VERSION 5.8 ;
BUSBITCHARS "[]" ;
DIVIDERCHAR "/" ;
UNITS
    DATABASE MICRONS 1000 ;
END UNITS

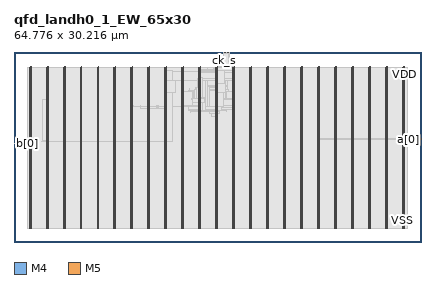
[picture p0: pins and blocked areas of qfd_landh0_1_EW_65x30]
MACRO qfd_landh0_1_EW_65x30
  FOREIGN qfd_landh0_1_EW_65x30 0 0 ;
  CLASS BLOCK ;
  SIZE 64.776 BY 30.216 ;
  PIN a[0]
    DIRECTION INPUT ;
    USE SIGNAL ;
    PORT
      LAYER M4 ;
        RECT  64.692 16.368 64.776 16.392 ;
    END
  END a[0]
  PIN b[0]
    DIRECTION OUTPUT ;
    USE SIGNAL ;
    PORT
      LAYER M4 ;
        RECT  0 15.6 0.084 15.624 ;
    END
  END b[0]
  PIN ck
    DIRECTION INPUT ;
    USE SIGNAL ;
    PORT
      LAYER M5 ;
        RECT  33.36 30.132 33.384 30.216 ;
    END
  END ck
  PIN ck_s
    DIRECTION INPUT ;
    USE SIGNAL ;
    PORT
      LAYER M5 ;
        RECT  33.456 30.132 33.48 30.216 ;
    END
  END ck_s
  PIN en
    DIRECTION INPUT ;
    USE SIGNAL ;
    PORT
      LAYER M5 ;
        RECT  33.552 30.132 33.576 30.216 ;
    END
  END en
  PIN fault
    DIRECTION OUTPUT ;
    USE SIGNAL ;
    PORT
      LAYER M5 ;
        RECT  33.648 30.132 33.672 30.216 ;
    END
  END fault
  PIN k0
    DIRECTION INPUT ;
    USE SIGNAL ;
    PORT
      LAYER M5 ;
        RECT  33.744 30.132 33.768 30.216 ;
    END
  END k0
  PIN k1
    DIRECTION INPUT ;
    USE SIGNAL ;
    PORT
      LAYER M5 ;
        RECT  33.84 30.132 33.864 30.216 ;
    END
  END k1
  PIN k2
    DIRECTION INPUT ;
    USE SIGNAL ;
    PORT
      LAYER M5 ;
        RECT  33.936 30.132 33.96 30.216 ;
    END
  END k2
  PIN rs
    DIRECTION INPUT ;
    USE SIGNAL ;
    PORT
      LAYER M5 ;
        RECT  34.032 30.132 34.056 30.216 ;
    END
  END rs
  PIN tie_hi
    DIRECTION OUTPUT ;
    USE SIGNAL ;
    PORT
      LAYER M5 ;
        RECT  34.128 30.132 34.152 30.216 ;
    END
  END tie_hi
  PIN tie_lo
    DIRECTION OUTPUT ;
    USE SIGNAL ;
    PORT
      LAYER M5 ;
        RECT  34.224 30.132 34.248 30.216 ;
    END
  END tie_lo
  PIN VDD
    DIRECTION INOUT ;
    USE POWER ;
    PORT
      LAYER M5 ;
        RECT  61.992 2.151 62.112 27.833 ;
        RECT  59.292 2.151 59.412 27.833 ;
        RECT  56.592 2.151 56.712 27.833 ;
        RECT  53.892 2.151 54.012 27.833 ;
        RECT  51.192 2.151 51.312 27.833 ;
        RECT  48.492 2.151 48.612 27.833 ;
        RECT  45.792 2.151 45.912 27.833 ;
        RECT  43.092 2.151 43.212 27.833 ;
        RECT  40.392 2.151 40.512 27.833 ;
        RECT  37.692 2.151 37.812 27.833 ;
        RECT  34.992 2.151 35.112 27.833 ;
        RECT  32.292 2.151 32.412 27.833 ;
        RECT  29.592 2.151 29.712 27.833 ;
        RECT  26.892 2.151 27.012 27.833 ;
        RECT  24.192 2.151 24.312 27.833 ;
        RECT  21.492 2.151 21.612 27.833 ;
        RECT  18.792 2.151 18.912 27.833 ;
        RECT  16.092 2.151 16.212 27.833 ;
        RECT  13.392 2.151 13.512 27.833 ;
        RECT  10.692 2.151 10.812 27.833 ;
        RECT  7.992 2.151 8.112 27.833 ;
        RECT  5.292 2.151 5.412 27.833 ;
        RECT  2.592 2.151 2.712 27.833 ;
    END
  END VDD
  PIN VSS
    DIRECTION INOUT ;
    USE GROUND ;
    PORT
      LAYER M5 ;
        RECT  61.8 2.137 61.92 27.819 ;
        RECT  59.1 2.137 59.22 27.819 ;
        RECT  56.4 2.137 56.52 27.819 ;
        RECT  53.7 2.137 53.82 27.819 ;
        RECT  51 2.137 51.12 27.819 ;
        RECT  48.3 2.137 48.42 27.819 ;
        RECT  45.6 2.137 45.72 27.819 ;
        RECT  42.9 2.137 43.02 27.819 ;
        RECT  40.2 2.137 40.32 27.819 ;
        RECT  37.5 2.137 37.62 27.819 ;
        RECT  34.8 2.137 34.92 27.819 ;
        RECT  32.1 2.137 32.22 27.819 ;
        RECT  29.4 2.137 29.52 27.819 ;
        RECT  26.7 2.137 26.82 27.819 ;
        RECT  24 2.137 24.12 27.819 ;
        RECT  21.3 2.137 21.42 27.819 ;
        RECT  18.6 2.137 18.72 27.819 ;
        RECT  15.9 2.137 16.02 27.819 ;
        RECT  13.2 2.137 13.32 27.819 ;
        RECT  10.5 2.137 10.62 27.819 ;
        RECT  7.8 2.137 7.92 27.819 ;
        RECT  5.1 2.137 5.22 27.819 ;
        RECT  2.4 2.137 2.52 27.819 ;
    END
  END VSS
  OBS
    LAYER RVTN ;
     RECT  2.16 2.16 62.586 2.295 ;
     RECT  2.16 2.565 62.586 2.835 ;
     RECT  2.16 3.105 62.586 3.375 ;
     RECT  2.16 3.645 62.586 3.915 ;
     RECT  2.16 4.185 62.586 4.455 ;
     RECT  2.16 4.725 62.586 4.995 ;
     RECT  2.16 5.265 62.586 5.535 ;
     RECT  2.16 5.805 62.586 6.075 ;
     RECT  2.16 6.345 62.586 6.615 ;
     RECT  2.16 6.885 62.586 7.155 ;
     RECT  2.16 7.425 62.586 7.695 ;
     RECT  2.16 7.965 62.586 8.235 ;
     RECT  2.16 8.505 62.586 8.775 ;
     RECT  2.16 9.045 62.586 9.315 ;
     RECT  2.16 9.585 62.586 9.855 ;
     RECT  2.16 10.125 62.586 10.395 ;
     RECT  2.16 10.665 62.586 10.935 ;
     RECT  2.16 11.205 62.586 11.475 ;
     RECT  2.16 11.745 62.586 12.015 ;
     RECT  2.16 12.285 62.586 12.555 ;
     RECT  2.16 12.825 62.586 13.095 ;
     RECT  2.16 13.365 62.586 13.635 ;
     RECT  2.16 13.905 62.586 14.175 ;
     RECT  2.16 14.445 62.586 14.715 ;
     RECT  2.16 14.985 62.586 15.255 ;
     RECT  2.16 15.525 62.586 15.795 ;
     RECT  2.16 16.065 62.586 16.335 ;
     RECT  2.16 16.605 62.586 16.875 ;
     RECT  2.16 17.145 62.586 17.415 ;
     RECT  2.16 17.685 62.586 17.955 ;
     RECT  2.16 18.225 62.586 18.495 ;
     RECT  2.16 18.765 62.586 19.035 ;
     RECT  2.16 19.305 62.586 19.575 ;
     RECT  2.16 19.845 62.586 20.115 ;
     RECT  2.16 20.385 62.586 20.655 ;
     RECT  2.16 20.925 62.586 21.195 ;
     RECT  2.16 21.465 62.586 21.735 ;
     RECT  2.16 22.005 62.586 22.275 ;
     RECT  2.16 22.545 62.586 22.815 ;
     RECT  2.16 23.085 62.586 23.355 ;
     RECT  2.16 23.625 62.586 23.895 ;
     RECT  2.16 24.165 62.586 24.435 ;
     RECT  2.16 24.705 62.586 24.975 ;
     RECT  2.16 25.245 62.586 25.515 ;
     RECT  2.16 25.785 62.586 26.055 ;
     RECT  2.16 26.325 62.586 26.595 ;
     RECT  2.16 26.865 62.586 27.135 ;
     RECT  2.16 27.405 62.586 27.675 ;
    LAYER RVTP ;
     RECT  2.16 2.295 62.586 2.565 ;
     RECT  2.16 2.835 62.586 3.105 ;
     RECT  2.16 3.375 62.586 3.645 ;
     RECT  2.16 3.915 62.586 4.185 ;
     RECT  2.16 4.455 62.586 4.725 ;
     RECT  2.16 4.995 62.586 5.265 ;
     RECT  2.16 5.535 62.586 5.805 ;
     RECT  2.16 6.075 62.586 6.345 ;
     RECT  2.16 6.615 62.586 6.885 ;
     RECT  2.16 7.155 62.586 7.425 ;
     RECT  2.16 7.695 62.586 7.965 ;
     RECT  2.16 8.235 62.586 8.505 ;
     RECT  2.16 8.775 62.586 9.045 ;
     RECT  2.16 9.315 62.586 9.585 ;
     RECT  2.16 9.855 62.586 10.125 ;
     RECT  2.16 10.395 62.586 10.665 ;
     RECT  2.16 10.935 62.586 11.205 ;
     RECT  2.16 11.475 62.586 11.745 ;
     RECT  2.16 12.015 62.586 12.285 ;
     RECT  2.16 12.555 62.586 12.825 ;
     RECT  2.16 13.095 62.586 13.365 ;
     RECT  2.16 13.635 62.586 13.905 ;
     RECT  2.16 14.175 62.586 14.445 ;
     RECT  2.16 14.715 62.586 14.985 ;
     RECT  2.16 15.255 62.586 15.525 ;
     RECT  2.16 15.795 62.586 16.065 ;
     RECT  2.16 16.335 62.586 16.605 ;
     RECT  2.16 16.875 62.586 17.145 ;
     RECT  2.16 17.415 62.586 17.685 ;
     RECT  2.16 17.955 62.586 18.225 ;
     RECT  2.16 18.495 62.586 18.765 ;
     RECT  2.16 19.035 62.586 19.305 ;
     RECT  2.16 19.575 62.586 19.845 ;
     RECT  2.16 20.115 62.586 20.385 ;
     RECT  2.16 20.655 62.586 20.925 ;
     RECT  2.16 21.195 62.586 21.465 ;
     RECT  2.16 21.735 62.586 22.005 ;
     RECT  2.16 22.275 62.586 22.545 ;
     RECT  2.16 22.815 62.586 23.085 ;
     RECT  2.16 23.355 62.586 23.625 ;
     RECT  2.16 23.895 62.586 24.165 ;
     RECT  2.16 24.435 62.586 24.705 ;
     RECT  2.16 24.975 62.586 25.245 ;
     RECT  2.16 25.515 62.586 25.785 ;
     RECT  2.16 26.055 62.586 26.325 ;
     RECT  2.16 26.595 62.586 26.865 ;
     RECT  2.16 27.135 62.586 27.405 ;
     RECT  2.16 27.675 62.586 27.81 ;
    LAYER M1 ;
     RECT  2.16 2.151 62.586 27.819 ;
    LAYER M2 ;
     RECT  2.16 2.151 62.586 27.819 ;
    LAYER M3 ;
     RECT  2.415 2.143 2.505 2.413 ;
     RECT  5.115 2.143 5.205 2.413 ;
     RECT  7.815 2.143 7.905 2.413 ;
     RECT  10.515 2.143 10.605 2.413 ;
     RECT  13.215 2.143 13.305 2.413 ;
     RECT  15.915 2.143 16.005 2.413 ;
     RECT  18.615 2.143 18.705 2.413 ;
     RECT  21.315 2.143 21.405 2.413 ;
     RECT  24.015 2.143 24.105 2.413 ;
     RECT  26.715 2.143 26.805 2.413 ;
     RECT  29.415 2.143 29.505 2.413 ;
     RECT  32.115 2.143 32.205 2.413 ;
     RECT  34.815 2.143 34.905 2.413 ;
     RECT  37.515 2.143 37.605 2.413 ;
     RECT  40.215 2.143 40.305 2.413 ;
     RECT  42.915 2.143 43.005 2.413 ;
     RECT  45.615 2.143 45.705 2.413 ;
     RECT  48.315 2.143 48.405 2.413 ;
     RECT  51.015 2.143 51.105 2.413 ;
     RECT  53.715 2.143 53.805 2.413 ;
     RECT  56.415 2.143 56.505 2.413 ;
     RECT  59.115 2.143 59.205 2.413 ;
     RECT  61.815 2.143 61.905 2.413 ;
     RECT  2.415 2.413 2.697 15.595 ;
     RECT  2.304 15.595 2.697 15.827 ;
     RECT  4.32 15.961 4.338 16.013 ;
     RECT  5.115 2.413 5.397 16.141 ;
     RECT  48.315 2.413 48.597 16.363 ;
     RECT  32.115 2.413 32.397 18.121 ;
     RECT  48.276 16.363 48.597 18.185 ;
     RECT  32.004 18.121 32.397 19.921 ;
     RECT  31.392 19.921 32.397 20.425 ;
     RECT  31.14 20.425 32.397 20.461 ;
     RECT  28.008 20.623 28.026 20.731 ;
     RECT  29.415 2.413 29.697 20.731 ;
     RECT  31.14 20.461 32.67 20.731 ;
     RECT  33.804 20.731 33.822 20.893 ;
     RECT  28.008 20.731 32.67 20.929 ;
     RECT  33.624 20.893 33.822 20.929 ;
     RECT  27.828 20.929 33.822 21.001 ;
     RECT  34.815 2.413 35.097 21.001 ;
     RECT  18.615 2.413 18.897 21.499 ;
     RECT  22.788 21.211 22.806 21.499 ;
     RECT  22.68 21.499 22.914 21.629 ;
     RECT  18.615 21.499 18.99 21.659 ;
     RECT  20.088 21.211 20.106 21.659 ;
     RECT  27.828 21.001 35.097 21.677 ;
     RECT  4.464 16.141 5.397 22.649 ;
     RECT  28.332 21.677 35.097 22.741 ;
     RECT  28.224 22.741 35.097 22.781 ;
     RECT  25.632 23.791 25.65 23.837 ;
     RECT  24.015 2.413 24.297 23.851 ;
     RECT  28.332 22.781 35.097 23.855 ;
     RECT  33.12 23.855 35.097 23.927 ;
     RECT  28.332 23.855 32.397 23.947 ;
     RECT  24.015 23.851 24.498 24.091 ;
     RECT  27.792 23.947 32.397 24.125 ;
     RECT  24.015 24.091 25.038 24.131 ;
     RECT  28.728 24.125 32.397 24.221 ;
     RECT  33.12 23.927 34.074 24.269 ;
     RECT  27.936 24.125 27.954 24.359 ;
     RECT  28.836 24.221 32.397 24.503 ;
     RECT  29.088 24.503 32.397 24.509 ;
     RECT  29.124 24.509 32.397 24.781 ;
     RECT  33.12 24.269 34.002 24.781 ;
     RECT  24.015 24.131 24.498 24.859 ;
     RECT  24.015 24.859 25.146 24.899 ;
     RECT  24.015 24.899 24.498 24.935 ;
     RECT  29.124 24.781 34.002 24.935 ;
     RECT  29.232 24.935 34.002 25.717 ;
     RECT  34.815 23.927 35.097 25.717 ;
     RECT  28.98 25.717 35.097 25.757 ;
     RECT  29.232 25.757 35.097 25.979 ;
     RECT  29.415 25.979 35.097 26.051 ;
     RECT  29.415 26.051 32.397 26.905 ;
     RECT  33.156 26.051 35.097 26.905 ;
     RECT  29.415 26.905 35.097 27.329 ;
     RECT  29.415 27.329 32.49 27.365 ;
     RECT  30.564 27.365 30.762 27.401 ;
     RECT  31.536 27.365 32.397 27.509 ;
     RECT  2.415 15.827 2.697 27.557 ;
     RECT  5.115 22.649 5.397 27.557 ;
     RECT  7.815 2.413 8.097 27.557 ;
     RECT  10.515 2.413 10.797 27.557 ;
     RECT  13.215 2.413 13.497 27.557 ;
     RECT  15.915 2.413 16.197 27.557 ;
     RECT  18.615 21.659 18.897 27.557 ;
     RECT  21.315 2.413 21.597 27.557 ;
     RECT  24.015 24.935 24.297 27.557 ;
     RECT  26.715 2.413 26.997 27.557 ;
     RECT  29.415 27.365 29.697 27.557 ;
     RECT  33.228 27.329 35.097 27.557 ;
     RECT  37.515 2.413 37.797 27.557 ;
     RECT  40.215 2.413 40.497 27.557 ;
     RECT  42.915 2.413 43.197 27.557 ;
     RECT  45.615 2.413 45.897 27.557 ;
     RECT  48.315 18.185 48.597 27.557 ;
     RECT  51.015 2.413 51.297 27.557 ;
     RECT  53.715 2.413 53.997 27.557 ;
     RECT  56.415 2.413 56.697 27.557 ;
     RECT  59.115 2.413 59.397 27.557 ;
     RECT  61.815 2.413 62.097 27.557 ;
     RECT  33.228 27.557 34.254 27.599 ;
     RECT  31.68 27.509 32.397 27.635 ;
     RECT  30.744 27.401 30.762 27.707 ;
     RECT  32.076 27.635 32.397 27.707 ;
     RECT  2.607 27.557 2.697 27.827 ;
     RECT  5.307 27.557 5.397 27.827 ;
     RECT  8.007 27.557 8.097 27.827 ;
     RECT  10.707 27.557 10.797 27.827 ;
     RECT  13.407 27.557 13.497 27.827 ;
     RECT  16.107 27.557 16.197 27.827 ;
     RECT  18.807 27.557 18.897 27.827 ;
     RECT  21.507 27.557 21.597 27.827 ;
     RECT  24.207 27.557 24.297 27.827 ;
     RECT  26.907 27.557 26.997 27.827 ;
     RECT  29.607 27.557 29.697 27.827 ;
     RECT  32.307 27.707 32.397 27.827 ;
     RECT  35.007 27.557 35.097 27.827 ;
     RECT  37.707 27.557 37.797 27.827 ;
     RECT  40.407 27.557 40.497 27.827 ;
     RECT  43.107 27.557 43.197 27.827 ;
     RECT  45.807 27.557 45.897 27.827 ;
     RECT  48.507 27.557 48.597 27.827 ;
     RECT  51.207 27.557 51.297 27.827 ;
     RECT  53.907 27.557 53.997 27.827 ;
     RECT  56.607 27.557 56.697 27.827 ;
     RECT  59.307 27.557 59.397 27.827 ;
     RECT  62.007 27.557 62.097 27.827 ;
     RECT  33.552 27.599 34.254 27.965 ;
     RECT  33.624 27.965 34.254 30.029 ;
     RECT  33.624 30.029 34.218 30.125 ;
    LAYER M4 ;
     RECT  0.06 15.6 2.408 15.624 ;
     RECT  2.408 2.148 2.512 27.552 ;
     RECT  2.512 2.418 2.6 27.552 ;
     RECT  2.6 2.418 2.704 27.822 ;
     RECT  4.309 15.984 5.108 16.008 ;
     RECT  5.108 2.148 5.212 27.552 ;
     RECT  5.212 2.418 5.3 27.552 ;
     RECT  5.3 2.418 5.404 27.822 ;
     RECT  5.404 15.984 7.808 16.008 ;
     RECT  7.808 2.148 7.912 27.552 ;
     RECT  7.912 2.418 8 27.552 ;
     RECT  8 2.418 8.104 27.822 ;
     RECT  8.104 15.984 10.508 16.008 ;
     RECT  10.508 2.148 10.612 27.552 ;
     RECT  10.612 2.418 10.7 27.552 ;
     RECT  10.7 2.418 10.804 27.822 ;
     RECT  10.804 15.984 13.208 16.008 ;
     RECT  13.208 2.148 13.312 27.552 ;
     RECT  13.312 2.418 13.4 27.552 ;
     RECT  13.4 2.418 13.504 27.822 ;
     RECT  13.504 15.984 15.908 16.008 ;
     RECT  15.908 2.148 16.012 27.552 ;
     RECT  16.012 2.418 16.1 27.552 ;
     RECT  16.1 2.418 16.204 27.822 ;
     RECT  16.204 15.984 18.608 16.008 ;
     RECT  18.608 2.148 18.712 27.552 ;
     RECT  18.712 2.418 18.8 27.552 ;
     RECT  18.8 2.418 18.904 27.822 ;
     RECT  18.904 21.504 20.077 21.528 ;
     RECT  18.904 15.984 21.308 16.008 ;
     RECT  20.077 21.216 21.308 21.528 ;
     RECT  21.308 2.148 21.412 27.552 ;
     RECT  21.412 2.418 21.5 27.552 ;
     RECT  21.5 2.418 21.604 27.822 ;
     RECT  21.604 21.216 22.669 21.528 ;
     RECT  22.669 21.216 22.925 21.624 ;
     RECT  21.604 15.984 24.008 16.008 ;
     RECT  22.925 21.216 24.008 21.528 ;
     RECT  24.008 2.148 24.112 27.552 ;
     RECT  24.112 2.418 24.2 27.552 ;
     RECT  24.2 2.418 24.304 27.822 ;
     RECT  24.304 21.216 24.467 21.528 ;
     RECT  24.304 23.856 24.509 24.888 ;
     RECT  24.304 15.984 25.187 16.008 ;
     RECT  24.509 24.096 25.187 24.888 ;
     RECT  25.187 24.096 25.58 24.12 ;
     RECT  25.58 23.808 25.667 24.12 ;
     RECT  24.467 21.504 26.708 21.528 ;
     RECT  25.621 25.728 26.708 25.752 ;
     RECT  24.304 27.168 26.708 27.192 ;
     RECT  26.708 2.148 26.812 27.552 ;
     RECT  26.812 2.418 26.9 27.552 ;
     RECT  26.9 2.418 27.004 27.822 ;
     RECT  28.213 22.752 28.501 22.776 ;
     RECT  27.004 23.952 28.501 23.976 ;
     RECT  28.501 22.752 28.717 23.976 ;
     RECT  28.717 22.752 29.077 24.216 ;
     RECT  29.077 22.752 29.269 24.504 ;
     RECT  27.004 25.728 29.269 25.752 ;
     RECT  27.004 21.504 29.408 21.672 ;
     RECT  29.269 22.752 29.408 26.136 ;
     RECT  27.004 27.168 29.408 27.192 ;
     RECT  29.408 2.148 29.512 27.552 ;
     RECT  29.512 2.418 29.6 27.552 ;
     RECT  29.6 2.418 29.704 27.822 ;
     RECT  29.704 20.88 30.017 26.136 ;
     RECT  30.017 20.88 30.449 25.752 ;
     RECT  30.449 21.504 30.809 25.752 ;
     RECT  30.809 21.504 31.133 24.696 ;
     RECT  29.704 27.168 31.993 27.192 ;
     RECT  31.133 21.504 32.108 24.024 ;
     RECT  30.809 25.728 32.108 25.752 ;
     RECT  31.993 26.736 32.108 27.192 ;
     RECT  32.108 2.148 32.212 27.552 ;
     RECT  32.212 2.418 32.3 27.552 ;
     RECT  32.3 2.418 32.404 27.822 ;
     RECT  32.404 20.976 32.573 23.928 ;
     RECT  32.573 20.976 33.011 22.824 ;
     RECT  33.011 20.976 33.052 21.528 ;
     RECT  32.404 25.728 33.244 26.616 ;
     RECT  33.052 21.408 33.395 21.528 ;
     RECT  33.244 25.728 33.469 25.752 ;
     RECT  32.573 23.904 33.491 23.928 ;
     RECT  33.5 27.936 33.587 27.96 ;
     RECT  33.011 22.752 33.589 22.824 ;
     RECT  33.469 25.104 33.635 25.752 ;
     RECT  33.613 30.096 33.649 30.12 ;
     RECT  33.635 25.728 33.653 25.752 ;
     RECT  33.589 22.752 33.761 23.736 ;
     RECT  33.649 29.664 33.875 30.12 ;
     RECT  33.875 30 34.229 30.12 ;
     RECT  34.229 30 34.265 30.024 ;
     RECT  33.395 21.408 34.808 21.432 ;
     RECT  33.761 22.752 34.808 22.776 ;
     RECT  33.757 27.216 34.808 27.336 ;
     RECT  34.808 2.148 34.912 27.552 ;
     RECT  34.912 2.418 35 27.552 ;
     RECT  35 2.418 35.104 27.822 ;
     RECT  37.508 2.148 37.612 27.552 ;
     RECT  37.612 2.418 37.7 27.552 ;
     RECT  37.7 2.418 37.804 27.822 ;
     RECT  40.208 2.148 40.312 27.552 ;
     RECT  40.312 2.418 40.4 27.552 ;
     RECT  40.4 2.418 40.504 27.822 ;
     RECT  42.908 2.148 43.012 27.552 ;
     RECT  43.012 2.418 43.1 27.552 ;
     RECT  43.1 2.418 43.204 27.822 ;
     RECT  45.608 2.148 45.712 27.552 ;
     RECT  45.712 2.418 45.8 27.552 ;
     RECT  45.8 2.418 45.904 27.822 ;
     RECT  48.265 16.368 48.308 16.392 ;
     RECT  48.308 2.148 48.412 27.552 ;
     RECT  48.412 2.418 48.5 27.552 ;
     RECT  48.5 2.418 48.604 27.822 ;
     RECT  48.604 16.368 51.008 16.392 ;
     RECT  51.008 2.148 51.112 27.552 ;
     RECT  51.112 2.418 51.2 27.552 ;
     RECT  51.2 2.418 51.304 27.822 ;
     RECT  51.304 16.368 53.708 16.392 ;
     RECT  53.708 2.148 53.812 27.552 ;
     RECT  53.812 2.418 53.9 27.552 ;
     RECT  53.9 2.418 54.004 27.822 ;
     RECT  54.004 16.368 56.408 16.392 ;
     RECT  56.408 2.148 56.512 27.552 ;
     RECT  56.512 2.418 56.6 27.552 ;
     RECT  56.6 2.418 56.704 27.822 ;
     RECT  56.704 16.368 59.108 16.392 ;
     RECT  59.108 2.148 59.212 27.552 ;
     RECT  59.212 2.418 59.3 27.552 ;
     RECT  59.3 2.418 59.404 27.822 ;
     RECT  59.404 16.368 61.808 16.392 ;
     RECT  61.808 2.148 61.912 27.552 ;
     RECT  61.912 2.418 62 27.552 ;
     RECT  62 2.418 62.104 27.822 ;
     RECT  62.104 16.368 64.716 16.392 ;
    LAYER M5 ;
     RECT  2.4 2.137 2.52 2.151 ;
     RECT  5.1 2.137 5.22 2.151 ;
     RECT  7.8 2.137 7.92 2.151 ;
     RECT  10.5 2.137 10.62 2.151 ;
     RECT  13.2 2.137 13.32 2.151 ;
     RECT  15.9 2.137 16.02 2.151 ;
     RECT  18.6 2.137 18.72 2.151 ;
     RECT  21.3 2.137 21.42 2.151 ;
     RECT  24 2.137 24.12 2.151 ;
     RECT  26.7 2.137 26.82 2.151 ;
     RECT  29.4 2.137 29.52 2.151 ;
     RECT  32.1 2.137 32.22 2.151 ;
     RECT  34.8 2.137 34.92 2.151 ;
     RECT  37.5 2.137 37.62 2.151 ;
     RECT  40.2 2.137 40.32 2.151 ;
     RECT  42.9 2.137 43.02 2.151 ;
     RECT  45.6 2.137 45.72 2.151 ;
     RECT  48.3 2.137 48.42 2.151 ;
     RECT  51 2.137 51.12 2.151 ;
     RECT  53.7 2.137 53.82 2.151 ;
     RECT  56.4 2.137 56.52 2.151 ;
     RECT  59.1 2.137 59.22 2.151 ;
     RECT  61.8 2.137 61.92 2.151 ;
     RECT  24 2.151 24.312 15.973 ;
     RECT  32.1 2.151 32.412 20.965 ;
     RECT  22.8 21.205 22.824 21.491 ;
     RECT  32.1 20.965 33 21.493 ;
     RECT  29.4 2.151 29.712 21.637 ;
     RECT  28.464 21.637 29.712 22.165 ;
     RECT  28.464 22.165 30.216 22.787 ;
     RECT  29.28 22.787 30.216 23.027 ;
     RECT  32.1 21.493 33.384 23.701 ;
     RECT  24 15.973 25.176 23.797 ;
     RECT  30.768 24.661 30.792 24.803 ;
     RECT  32.1 23.701 33.624 25.139 ;
     RECT  24 23.797 25.656 25.763 ;
     RECT  29.28 23.027 29.712 26.147 ;
     RECT  24 25.763 25.176 27.203 ;
     RECT  32.1 25.139 33.48 27.205 ;
     RECT  34.8 2.151 35.112 27.205 ;
     RECT  2.4 2.151 2.712 27.819 ;
     RECT  5.1 2.151 5.412 27.819 ;
     RECT  7.8 2.151 8.112 27.819 ;
     RECT  10.5 2.151 10.812 27.819 ;
     RECT  13.2 2.151 13.512 27.819 ;
     RECT  15.9 2.151 16.212 27.819 ;
     RECT  18.6 2.151 18.912 27.819 ;
     RECT  21.3 2.151 21.612 27.819 ;
     RECT  24 27.203 24.312 27.819 ;
     RECT  26.7 2.151 27.012 27.819 ;
     RECT  29.4 26.147 29.712 27.819 ;
     RECT  32.1 27.205 35.112 27.819 ;
     RECT  37.5 2.151 37.812 27.819 ;
     RECT  40.2 2.151 40.512 27.819 ;
     RECT  42.9 2.151 43.212 27.819 ;
     RECT  45.6 2.151 45.912 27.819 ;
     RECT  48.3 2.151 48.612 27.819 ;
     RECT  51 2.151 51.312 27.819 ;
     RECT  53.7 2.151 54.012 27.819 ;
     RECT  56.4 2.151 56.712 27.819 ;
     RECT  59.1 2.151 59.412 27.819 ;
     RECT  61.8 2.151 62.112 27.819 ;
     RECT  2.592 27.819 2.712 27.833 ;
     RECT  5.292 27.819 5.412 27.833 ;
     RECT  7.992 27.819 8.112 27.833 ;
     RECT  10.692 27.819 10.812 27.833 ;
     RECT  13.392 27.819 13.512 27.833 ;
     RECT  16.092 27.819 16.212 27.833 ;
     RECT  18.792 27.819 18.912 27.833 ;
     RECT  21.492 27.819 21.612 27.833 ;
     RECT  24.192 27.819 24.312 27.833 ;
     RECT  26.892 27.819 27.012 27.833 ;
     RECT  29.592 27.819 29.712 27.833 ;
     RECT  32.292 27.819 35.112 27.833 ;
     RECT  37.692 27.819 37.812 27.833 ;
     RECT  40.392 27.819 40.512 27.833 ;
     RECT  43.092 27.819 43.212 27.833 ;
     RECT  45.792 27.819 45.912 27.833 ;
     RECT  48.492 27.819 48.612 27.833 ;
     RECT  51.192 27.819 51.312 27.833 ;
     RECT  53.892 27.819 54.012 27.833 ;
     RECT  56.592 27.819 56.712 27.833 ;
     RECT  59.292 27.819 59.412 27.833 ;
     RECT  61.992 27.819 62.112 27.833 ;
     RECT  33.36 27.833 34.056 29.989 ;
     RECT  33.36 29.989 34.248 30.16 ;
  END
END qfd_landh0_1_EW_65x30
END LIBRARY
